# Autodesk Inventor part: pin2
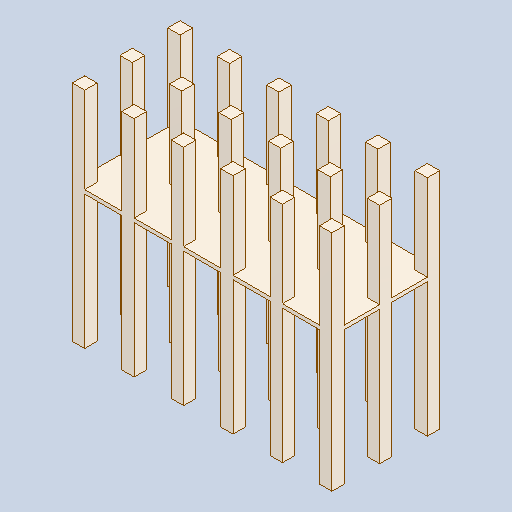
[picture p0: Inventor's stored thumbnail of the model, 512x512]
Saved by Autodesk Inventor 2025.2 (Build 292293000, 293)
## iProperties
Created: 2025-04
Part Number: pin2
Material: Generic
Description: PART--DESC
Document SubType Name: Modeling
Designer: BennF
Density: 1 g/cm^3
Appearance: Default
Author: BennF
Revision Number: NONE
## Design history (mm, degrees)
feature "Solid"
body "Solid1"
